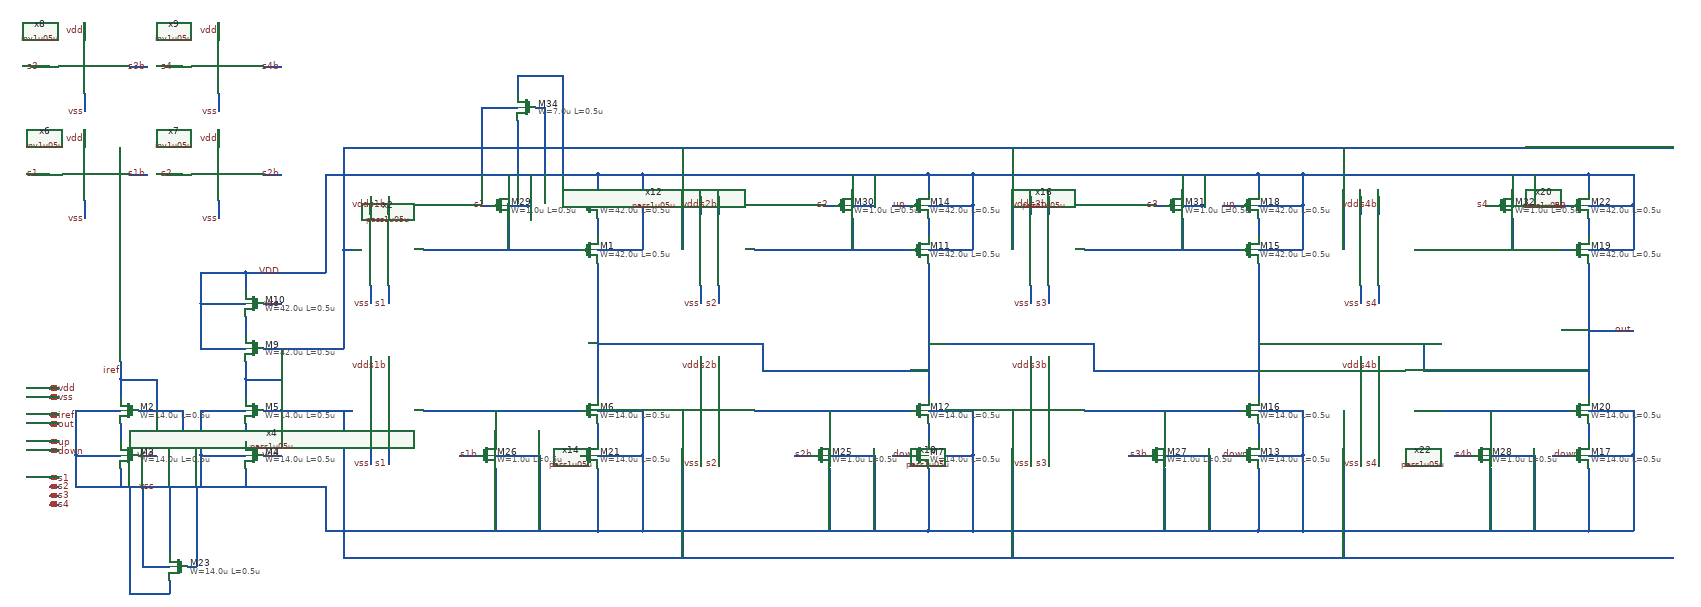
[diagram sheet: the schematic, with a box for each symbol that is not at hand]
v {xschem version=3.4.7 file_version=1.2}
G {}
K {}
V {}
S {}
E {}
P 4 1 -3240 -740 {}
N -2890 -1040 -2870 -1040 {lab=vdd}
N -2890 -1020 -2870 -1020 {lab=vss}
N -2890 -920 -2870 -920 {lab=up}
N -2890 -900 -2870 -900 {lab=down}
N -2890 -980 -2870 -980 {lab=iref}
N -2890 -960 -2870 -960 {lab=out}
N -2730 -860 -2730 -820 {lab=vss}
N -2820 -890 -2730 -890 {lab=vss}
N -2830 -890 -2820 -890 {lab=vss}
N -2830 -890 -2830 -820 {lab=vss}
N -2830 -820 -2730 -820 {lab=vss}
N -2830 -990 -2730 -990 {lab=vss}
N -2830 -990 -2830 -890 {lab=vss}
N -2730 -960 -2730 -920 {lab=#net1}
N -2690 -890 -2650 -890 {lab=vdd}
N -2690 -990 -2590 -990 {lab=iref}
N -2650 -1060 -2650 -990 {lab=iref}
N -2730 -1060 -2650 -1060 {lab=iref}
N -2730 -1060 -2730 -1020 {lab=iref}
N -2730 -1100 -2730 -1060 {lab=iref}
N -2450 -860 -2450 -820 {lab=vss}
N -2540 -890 -2450 -890 {lab=vss}
N -2550 -890 -2540 -890 {lab=vss}
N -2550 -890 -2550 -820 {lab=vss}
N -2550 -820 -2450 -820 {lab=vss}
N -2550 -990 -2450 -990 {lab=vss}
N -2550 -990 -2550 -890 {lab=vss}
N -2450 -960 -2450 -920 {lab=#net2}
N -2410 -890 -2370 -890 {lab=vdd}
N -2450 -1060 -2450 -1020 {lab=#net3}
N -2590 -990 -2590 -940 {lab=iref}
N -2590 -940 -2370 -940 {lab=iref}
N -2370 -990 -2370 -940 {lab=iref}
N -2410 -990 -2370 -990 {lab=iref}
N -1660 -860 -1660 -820 {lab=vss}
N -1660 -890 -1570 -890 {lab=vss}
N -1570 -890 -1560 -890 {lab=vss}
N -1560 -890 -1560 -820 {lab=vss}
N -1660 -990 -1560 -990 {lab=vss}
N -1560 -990 -1560 -890 {lab=vss}
N -1660 -960 -1660 -920 {lab=#net4}
N -1740 -890 -1700 -890 {lab=down}
N -1740 -990 -1700 -990 {lab=#net5}
N -2730 -820 -2550 -820 {lab=vss}
N -2370 -990 -2350 -990 {lab=iref}
N -2450 -820 -2270 -820 {lab=vss}
N -2410 -1130 -2310 -1130 {lab=#net3}
N -2450 -1100 -2450 -1060 {lab=#net3}
N -2450 -1060 -2370 -1060 {lab=#net3}
N -2370 -1130 -2370 -1060 {lab=#net3}
N -2450 -1200 -2450 -1160 {lab=#net6}
N -1660 -1420 -1660 -1380 {lab=#net7}
N -2410 -1230 -2370 -1230 {lab=vss}
N -1740 -1450 -1700 -1450 {lab=up}
N -2550 -1130 -2450 -1130 {lab=VDD}
N -2550 -1230 -2550 -1130 {lab=VDD}
N -2550 -1230 -2450 -1230 {lab=VDD}
N -1660 -1350 -1560 -1350 {lab=VDD}
N -1560 -1450 -1560 -1350 {lab=VDD}
N -1660 -1450 -1560 -1450 {lab=VDD}
N -1560 -1520 -1560 -1450 {lab=VDD}
N -1660 -1520 -1560 -1520 {lab=VDD}
N -1660 -1520 -1660 -1480 {lab=VDD}
N -2450 -1300 -2270 -1300 {lab=VDD}
N -2450 -1300 -2450 -1260 {lab=VDD}
N -2550 -1300 -2450 -1300 {lab=VDD}
N -2550 -1300 -2550 -1230 {lab=VDD}
N 560 -1170 660 -1170 {lab=out}
N -2350 -990 -2310 -990 {lab=iref}
N -2270 -1520 -2270 -1300 {lab=VDD}
N -2130 -1270 -2130 -1230 {lab=s1}
N -2170 -1270 -2170 -1230 {lab=vss}
N -2170 -1470 -2170 -1430 {lab=vdd}
N -2130 -1470 -2130 -1430 {lab=s1b}
N -2130 -910 -2130 -870 {lab=s1}
N -2130 -1110 -2130 -1070 {lab=s1b}
N -1560 -820 -1560 -780 {lab=vss}
N -1660 -820 -1660 -780 {lab=vss}
N -2310 -1130 -2230 -1130 {lab=#net3}
N -2230 -1350 -2230 -1130 {lab=#net3}
N -2230 -1350 -2210 -1350 {lab=#net3}
N -2050 -1350 -1770 -1350 {lab=#net8}
N -2310 -990 -2210 -990 {lab=iref}
N -2270 -1520 -1730 -1520 {lab=VDD}
N -2050 -990 -1950 -990 {lab=#net5}
N -2270 -820 -2270 -720 {lab=vss}
N -2270 -720 -1660 -720 {lab=vss}
N -1660 -780 -1660 -720 {lab=vss}
N -1560 -780 -1560 -720 {lab=vss}
N -1660 -720 -1560 -720 {lab=vss}
N -1950 -990 -1740 -990 {lab=#net5}
N -1730 -1520 -1660 -1520 {lab=VDD}
N -1770 -1350 -1700 -1350 {lab=#net8}
N -1660 -1320 -1660 -1020 {lab=out}
N -2890 -800 -2870 -800 {lab=s3}
N -2890 -780 -2870 -780 {lab=s4}
N -2890 -840 -2870 -840 {lab=s1}
N -2890 -820 -2870 -820 {lab=s2}
N -2710 -1520 -2670 -1520 {lab=s1b}
N -2930 -1520 -2890 -1520 {lab=s1}
N -2410 -1520 -2370 -1520 {lab=s2b}
N -2630 -1520 -2590 -1520 {lab=s2}
N -2710 -1760 -2670 -1760 {lab=s3b}
N -2810 -1860 -2810 -1820 {lab=vdd}
N -2810 -1700 -2810 -1660 {lab=vss}
N -2930 -1760 -2890 -1760 {lab=s3}
N -2410 -1760 -2370 -1760 {lab=s4b}
N -2630 -1760 -2590 -1760 {lab=s4}
N -920 -860 -920 -820 {lab=vss}
N -920 -890 -830 -890 {lab=vss}
N -830 -890 -820 -890 {lab=vss}
N -820 -890 -820 -820 {lab=vss}
N -920 -990 -820 -990 {lab=vss}
N -820 -990 -820 -890 {lab=vss}
N -920 -960 -920 -920 {lab=#net9}
N -1000 -890 -960 -890 {lab=down}
N -1000 -990 -960 -990 {lab=#net10}
N -920 -1420 -920 -1380 {lab=#net11}
N -1000 -1450 -960 -1450 {lab=up}
N -920 -1350 -820 -1350 {lab=VDD}
N -820 -1450 -820 -1350 {lab=VDD}
N -920 -1450 -820 -1450 {lab=VDD}
N -820 -1520 -820 -1450 {lab=VDD}
N -920 -1520 -820 -1520 {lab=VDD}
N -920 -1520 -920 -1480 {lab=VDD}
N -1390 -1270 -1390 -1230 {lab=s2}
N -1390 -1470 -1390 -1430 {lab=s2b}
N -1390 -910 -1390 -870 {lab=s2}
N -1390 -1110 -1390 -1070 {lab=s2b}
N -820 -820 -820 -780 {lab=vss}
N -920 -820 -920 -780 {lab=vss}
N -1310 -1350 -1030 -1350 {lab=#net12}
N -1310 -990 -1210 -990 {lab=#net10}
N -920 -780 -920 -720 {lab=vss}
N -820 -780 -820 -720 {lab=vss}
N -920 -720 -820 -720 {lab=vss}
N -1210 -990 -1000 -990 {lab=#net10}
N -990 -1520 -920 -1520 {lab=VDD}
N -1030 -1350 -960 -1350 {lab=#net12}
N -920 -1320 -920 -1020 {lab=out}
N -180 -860 -180 -820 {lab=vss}
N -180 -890 -90 -890 {lab=vss}
N -90 -890 -80 -890 {lab=vss}
N -80 -890 -80 -820 {lab=vss}
N -180 -990 -80 -990 {lab=vss}
N -80 -990 -80 -890 {lab=vss}
N -180 -960 -180 -920 {lab=#net13}
N -260 -890 -220 -890 {lab=down}
N -260 -990 -220 -990 {lab=#net14}
N -180 -1420 -180 -1380 {lab=#net15}
N -260 -1450 -220 -1450 {lab=up}
N -180 -1350 -80 -1350 {lab=VDD}
N -80 -1450 -80 -1350 {lab=VDD}
N -180 -1450 -80 -1450 {lab=VDD}
N -80 -1520 -80 -1450 {lab=VDD}
N -180 -1520 -80 -1520 {lab=VDD}
N -180 -1520 -180 -1480 {lab=VDD}
N -650 -1270 -650 -1230 {lab=s3}
N -650 -1470 -650 -1430 {lab=s3b}
N -650 -910 -650 -870 {lab=s3}
N -650 -1110 -650 -1070 {lab=s3b}
N -80 -820 -80 -780 {lab=vss}
N -180 -820 -180 -780 {lab=vss}
N -570 -1350 -290 -1350 {lab=#net16}
N -570 -990 -470 -990 {lab=#net14}
N -180 -780 -180 -720 {lab=vss}
N -80 -780 -80 -720 {lab=vss}
N -180 -720 -80 -720 {lab=vss}
N -470 -990 -260 -990 {lab=#net14}
N -250 -1520 -180 -1520 {lab=VDD}
N -290 -1350 -220 -1350 {lab=#net16}
N -180 -1320 -180 -1020 {lab=out}
N 560 -860 560 -820 {lab=vss}
N 560 -890 650 -890 {lab=vss}
N 650 -890 660 -890 {lab=vss}
N 660 -890 660 -820 {lab=vss}
N 560 -990 660 -990 {lab=vss}
N 660 -990 660 -890 {lab=vss}
N 560 -960 560 -920 {lab=#net17}
N 480 -890 520 -890 {lab=down}
N 480 -990 520 -990 {lab=#net18}
N 560 -1420 560 -1380 {lab=#net19}
N 480 -1450 520 -1450 {lab=#net20}
N 560 -1350 660 -1350 {lab=VDD}
N 660 -1450 660 -1350 {lab=VDD}
N 560 -1450 660 -1450 {lab=VDD}
N 660 -1520 660 -1450 {lab=VDD}
N 560 -1520 660 -1520 {lab=VDD}
N 560 -1520 560 -1480 {lab=VDD}
N 90 -1270 90 -1230 {lab=s4}
N 90 -1470 90 -1430 {lab=s4b}
N 90 -910 90 -870 {lab=s4}
N 90 -1110 90 -1070 {lab=s4b}
N 660 -820 660 -780 {lab=vss}
N 560 -820 560 -780 {lab=vss}
N 170 -1350 450 -1350 {lab=#net21}
N 170 -990 270 -990 {lab=#net18}
N 560 -780 560 -720 {lab=vss}
N 660 -780 660 -720 {lab=vss}
N 560 -720 660 -720 {lab=vss}
N 270 -990 480 -990 {lab=#net18}
N 490 -1520 560 -1520 {lab=VDD}
N 450 -1350 520 -1350 {lab=#net21}
N 560 -1320 560 -1020 {lab=out}
N -1560 -720 -920 -720 {lab=vss}
N -820 -720 -180 -720 {lab=vss}
N -80 -720 560 -720 {lab=vss}
N -1560 -1520 -990 -1520 {lab=VDD}
N -820 -1520 -250 -1520 {lab=VDD}
N -80 -1520 490 -1520 {lab=VDD}
N -2230 -1580 -2230 -1350 {lab=#net3}
N 10 -1580 10 -1350 {lab=#net3}
N -730 -1580 -730 -1350 {lab=#net3}
N -1470 -1580 -1470 -1350 {lab=#net3}
N -2230 -990 -2230 -660 {lab=iref}
N 10 -990 10 -660 {lab=iref}
N -730 -990 -730 -660 {lab=iref}
N -1470 -990 -1470 -660 {lab=iref}
N -1660 -1140 -1290 -1140 {lab=out}
N -1290 -1140 -1290 -1080 {lab=out}
N -1290 -1080 -920 -1080 {lab=out}
N -920 -1140 -550 -1140 {lab=out}
N -550 -1140 -550 -1080 {lab=out}
N -550 -1080 -180 -1080 {lab=out}
N -180 -1140 190 -1140 {lab=out}
N 190 -1140 190 -1080 {lab=out}
N 190 -1080 560 -1080 {lab=out}
N -2230 -1580 750 -1580 {lab=#net3}
N -2230 -660 750 -660 {lab=iref}
N -2620 -820 -2620 -670 {lab=vss}
N -2680 -640 -2620 -640 {lab=vss}
N -2680 -820 -2680 -640 {lab=vss}
N -2580 -640 -2560 -640 {lab=vss}
N -2560 -820 -2560 -640 {lab=vss}
N -2620 -610 -2620 -580 {lab=vss}
N -2710 -580 -2620 -580 {lab=vss}
N -2710 -820 -2710 -580 {lab=vss}
N -1140 -890 -1050 -890 {lab=vss}
N -1050 -890 -1040 -890 {lab=vss}
N -1220 -890 -1180 -890 {lab=s2b}
N -1040 -890 -1040 -720 {lab=vss}
N -1140 -990 -1140 -920 {lab=#net10}
N -1140 -860 -1140 -720 {lab=vss}
N -1890 -890 -1800 -890 {lab=vss}
N -1800 -890 -1790 -890 {lab=vss}
N -1970 -890 -1930 -890 {lab=s1b}
N -1790 -890 -1790 -720 {lab=vss}
N -1890 -990 -1890 -920 {lab=#net5}
N -1890 -860 -1890 -720 {lab=vss}
N -390 -890 -300 -890 {lab=vss}
N -300 -890 -290 -890 {lab=vss}
N -470 -890 -430 -890 {lab=s3b}
N -290 -890 -290 -720 {lab=vss}
N -390 -990 -390 -920 {lab=#net14}
N -390 -860 -390 -720 {lab=vss}
N 340 -890 430 -890 {lab=vss}
N 430 -890 440 -890 {lab=vss}
N 260 -890 300 -890 {lab=s4b}
N 440 -890 440 -720 {lab=vss}
N 340 -990 340 -920 {lab=#net18}
N 340 -860 340 -720 {lab=vss}
N -1860 -1450 -1810 -1450 {lab=VDD}
N -1810 -1520 -1810 -1450 {lab=VDD}
N -1860 -1420 -1860 -1350 {lab=#net8}
N -1860 -1520 -1860 -1480 {lab=VDD}
N -1920 -1450 -1900 -1450 {lab=s1}
N -1090 -1450 -1040 -1450 {lab=VDD}
N -1040 -1520 -1040 -1450 {lab=VDD}
N -1090 -1420 -1090 -1350 {lab=#net12}
N -1090 -1520 -1090 -1480 {lab=VDD}
N -1150 -1450 -1130 -1450 {lab=s2}
N -350 -1450 -300 -1450 {lab=VDD}
N -300 -1520 -300 -1450 {lab=VDD}
N -350 -1420 -350 -1350 {lab=#net16}
N -350 -1520 -350 -1480 {lab=VDD}
N -410 -1450 -390 -1450 {lab=s3}
N 390 -1450 440 -1450 {lab=VDD}
N 440 -1520 440 -1450 {lab=VDD}
N 390 -1420 390 -1350 {lab=#net21}
N 390 -1520 390 -1480 {lab=VDD}
N 330 -1450 350 -1450 {lab=s4}
N -1840 -1740 -1840 -1700 {lab=VDD}
N -1920 -1670 -1840 -1670 {lab=VDD}
N -1920 -1670 -1920 -1520 {lab=VDD}
N -1840 -1640 -1840 -1520 {lab=VDD}
N -1840 -1740 -1740 -1740 {lab=VDD}
N -1740 -1740 -1740 -1520 {lab=VDD}
N -1800 -1670 -1780 -1670 {lab=VDD}
N -1780 -1670 -1780 -1520 {lab=VDD}
N -2230 -990 -2210 -990 {lab=iref}
N 50 -1270 50 -1230 {lab=vss}
N 50 -1470 50 -1430 {lab=vdd}
N -2810 -1620 -2810 -1580 {lab=vdd}
N -2810 -1460 -2810 -1420 {lab=vss}
N -2510 -1620 -2510 -1580 {lab=vdd}
N -2510 -1460 -2510 -1420 {lab=vss}
N -2510 -1860 -2510 -1820 {lab=vdd}
N -2510 -1700 -2510 -1660 {lab=vss}
N -2170 -910 -2170 -870 {lab=vss}
N -2170 -1110 -2170 -1070 {lab=vdd}
N -1430 -910 -1430 -870 {lab=vss}
N -1430 -1110 -1430 -1070 {lab=vdd}
N -1430 -1270 -1430 -1230 {lab=vss}
N -1430 -1470 -1430 -1430 {lab=vdd}
N -690 -1270 -690 -1230 {lab=vss}
N -690 -1470 -690 -1430 {lab=vdd}
N -690 -910 -690 -870 {lab=vss}
N -690 -1110 -690 -1070 {lab=vdd}
N 50 -910 50 -870 {lab=vss}
N 50 -1110 50 -1070 {lab=vdd}
C {devices/iopin.sym} -2890 -1040 0 1 {name=p2 lab=vdd}
C {devices/iopin.sym} -2890 -1020 0 1 {name=p3 lab=vss}
C {devices/iopin.sym} -2890 -920 0 1 {name=p5 lab=up}
C {devices/iopin.sym} -2890 -900 0 1 {name=p6 lab=down}
C {devices/iopin.sym} -2890 -980 0 1 {name=p1 lab=iref}
C {devices/iopin.sym} -2890 -960 0 1 {name=p4 lab=out}
C {devices/lab_wire.sym} -2650 -820 0 0 {name=p10 sig_type=std_logic lab=vss}
C {devices/lab_wire.sym} -2650 -890 0 0 {name=p7 sig_type=std_logic lab=vdd}
C {devices/lab_wire.sym} -2730 -1080 0 0 {name=p8 sig_type=std_logic lab=iref}
C {devices/lab_wire.sym} -2370 -890 0 0 {name=p11 sig_type=std_logic lab=vdd}
C {symbols/nfet_03v3.sym} -1680 -990 0 0 {name=M6
L=0.5u
W=14.0u
nf=2
m=1
ad="'int((nf+1)/2) * W/nf * 0.18u'"
pd="'2*int((nf+1)/2) * (W/nf + 0.18u)'"
as="'int((nf+2)/2) * W/nf * 0.18u'"
ps="'2*int((nf+2)/2) * (W/nf + 0.18u)'"
nrd="'0.18u / W'" nrs="'0.18u / W'"
sa=0 sb=0 sd=0
model=nfet_03v3
spiceprefix=X
}
C {devices/lab_wire.sym} -1740 -890 0 1 {name=p13 sig_type=std_logic lab=down}
C {symbols/pfet_03v3.sym} -1680 -1450 0 0 {name=M8
L=0.5u
W=42.0u
nf=6
m=1
ad="'int((nf+1)/2) * W/nf * 0.18u'"
pd="'2*int((nf+1)/2) * (W/nf + 0.18u)'"
as="'int((nf+2)/2) * W/nf * 0.18u'"
ps="'2*int((nf+2)/2) * (W/nf + 0.18u)'"
nrd="'0.18u / W'" nrs="'0.18u / W'"
sa=0 sb=0 sd=0
model=pfet_03v3
spiceprefix=X
}
C {symbols/pfet_03v3.sym} -2430 -1230 0 1 {name=M10
L=0.5u
W=42.0u
nf=6
m=1
ad="'int((nf+1)/2) * W/nf * 0.18u'"
pd="'2*int((nf+1)/2) * (W/nf + 0.18u)'"
as="'int((nf+2)/2) * W/nf * 0.18u'"
ps="'2*int((nf+2)/2) * (W/nf + 0.18u)'"
nrd="'0.18u / W'" nrs="'0.18u / W'"
sa=0 sb=0 sd=0
model=pfet_03v3
spiceprefix=X
}
C {devices/lab_wire.sym} -1740 -1450 0 1 {name=p9 sig_type=std_logic lab=up}
C {devices/lab_wire.sym} -2370 -1230 0 0 {name=p12 sig_type=std_logic lab=vss}
C {devices/lab_wire.sym} -2370 -1300 0 0 {name=p14 sig_type=std_logic lab=VDD}
C {devices/lab_wire.sym} 660 -1170 0 0 {name=p15 sig_type=std_logic lab=out}
C {libs/core_analog/pass1u05u/pass1u05u.sym} -2130 -1350 0 0 {name=x2}
C {devices/lab_wire.sym} -2170 -1230 0 0 {name=p22 sig_type=std_logic lab=vss}
C {devices/lab_wire.sym} -2170 -1450 0 0 {name=p23 sig_type=std_logic lab=vdd}
C {libs/core_analog/pass1u05u/pass1u05u.sym} -2130 -990 0 0 {name=x4}
C {devices/iopin.sym} -2890 -800 0 1 {name=p30 lab=s3}
C {devices/iopin.sym} -2890 -780 0 1 {name=p31 lab=s4}
C {devices/iopin.sym} -2890 -840 0 1 {name=p32 lab=s1}
C {devices/iopin.sym} -2890 -820 0 1 {name=p33 lab=s2}
C {libs/core_analog/inv1u05u/inv1u05u.sym} -2810 -1520 0 0 {name=x6}
C {devices/lab_wire.sym} -2910 -1520 0 0 {name=p36 sig_type=std_logic lab=s1}
C {devices/lab_wire.sym} -2670 -1520 0 0 {name=p37 sig_type=std_logic lab=s1b}
C {libs/core_analog/inv1u05u/inv1u05u.sym} -2510 -1520 0 0 {name=x7}
C {devices/lab_wire.sym} -2610 -1520 0 0 {name=p40 sig_type=std_logic lab=s2}
C {devices/lab_wire.sym} -2370 -1520 0 0 {name=p41 sig_type=std_logic lab=s2b}
C {libs/core_analog/inv1u05u/inv1u05u.sym} -2810 -1760 0 0 {name=x8}
C {devices/lab_wire.sym} -2910 -1760 0 0 {name=p44 sig_type=std_logic lab=s3}
C {devices/lab_wire.sym} -2670 -1760 0 0 {name=p45 sig_type=std_logic lab=s3b}
C {devices/lab_wire.sym} -2810 -1660 0 0 {name=p46 sig_type=std_logic lab=vss}
C {devices/lab_wire.sym} -2810 -1840 0 0 {name=p47 sig_type=std_logic lab=vdd}
C {libs/core_analog/inv1u05u/inv1u05u.sym} -2510 -1760 0 0 {name=x9}
C {devices/lab_wire.sym} -2610 -1760 0 0 {name=p48 sig_type=std_logic lab=s4}
C {devices/lab_wire.sym} -2370 -1760 0 0 {name=p49 sig_type=std_logic lab=s4b}
C {devices/lab_wire.sym} -2130 -1230 0 0 {name=p60 sig_type=std_logic lab=s1}
C {devices/lab_wire.sym} -2130 -1450 0 0 {name=p61 sig_type=std_logic lab=s1b}
C {devices/lab_wire.sym} -2130 -1090 0 0 {name=p64 sig_type=std_logic lab=s1b}
C {devices/lab_wire.sym} -2130 -870 0 0 {name=p66 sig_type=std_logic lab=s1}
C {symbols/nfet_03v3.sym} -940 -990 0 0 {name=M12
L=0.5u
W=14.0u
nf=2
m=2
ad="'int((nf+1)/2) * W/nf * 0.18u'"
pd="'2*int((nf+1)/2) * (W/nf + 0.18u)'"
as="'int((nf+2)/2) * W/nf * 0.18u'"
ps="'2*int((nf+2)/2) * (W/nf + 0.18u)'"
nrd="'0.18u / W'" nrs="'0.18u / W'"
sa=0 sb=0 sd=0
model=nfet_03v3
spiceprefix=X
}
C {devices/lab_wire.sym} -1000 -890 0 1 {name=p68 sig_type=std_logic lab=down}
C {symbols/pfet_03v3.sym} -940 -1450 0 0 {name=M14
L=0.5u
W=42.0u
nf=6
m=2
ad="'int((nf+1)/2) * W/nf * 0.18u'"
pd="'2*int((nf+1)/2) * (W/nf + 0.18u)'"
as="'int((nf+2)/2) * W/nf * 0.18u'"
ps="'2*int((nf+2)/2) * (W/nf + 0.18u)'"
nrd="'0.18u / W'" nrs="'0.18u / W'"
sa=0 sb=0 sd=0
model=pfet_03v3
spiceprefix=X
}
C {libs/core_analog/pass1u05u/pass1u05u.sym} -1390 -1350 0 0 {name=x12}
C {libs/core_analog/pass1u05u/pass1u05u.sym} -1390 -990 0 0 {name=x14}
C {devices/lab_wire.sym} -1390 -1230 0 0 {name=p80 sig_type=std_logic lab=s2}
C {devices/lab_wire.sym} -1390 -1450 0 0 {name=p81 sig_type=std_logic lab=s2b}
C {devices/lab_wire.sym} -1390 -1090 0 0 {name=p84 sig_type=std_logic lab=s2b}
C {devices/lab_wire.sym} -1390 -870 0 0 {name=p86 sig_type=std_logic lab=s2}
C {symbols/nfet_03v3.sym} -200 -990 0 0 {name=M16
L=0.5u
W=14.0u
nf=2
m=4
ad="'int((nf+1)/2) * W/nf * 0.18u'"
pd="'2*int((nf+1)/2) * (W/nf + 0.18u)'"
as="'int((nf+2)/2) * W/nf * 0.18u'"
ps="'2*int((nf+2)/2) * (W/nf + 0.18u)'"
nrd="'0.18u / W'" nrs="'0.18u / W'"
sa=0 sb=0 sd=0
model=nfet_03v3
spiceprefix=X
}
C {devices/lab_wire.sym} -260 -890 0 1 {name=p88 sig_type=std_logic lab=down}
C {symbols/pfet_03v3.sym} -200 -1450 0 0 {name=M18
L=0.5u
W=42.0u
nf=6
m=4
ad="'int((nf+1)/2) * W/nf * 0.18u'"
pd="'2*int((nf+1)/2) * (W/nf + 0.18u)'"
as="'int((nf+2)/2) * W/nf * 0.18u'"
ps="'2*int((nf+2)/2) * (W/nf + 0.18u)'"
nrd="'0.18u / W'" nrs="'0.18u / W'"
sa=0 sb=0 sd=0
model=pfet_03v3
spiceprefix=X
}
C {libs/core_analog/pass1u05u/pass1u05u.sym} -650 -1350 0 0 {name=x16}
C {libs/core_analog/pass1u05u/pass1u05u.sym} -650 -990 0 0 {name=x18}
C {devices/lab_wire.sym} -650 -1230 0 0 {name=p100 sig_type=std_logic lab=s3}
C {devices/lab_wire.sym} -650 -1450 0 0 {name=p101 sig_type=std_logic lab=s3b}
C {devices/lab_wire.sym} -650 -1090 0 0 {name=p104 sig_type=std_logic lab=s3b}
C {devices/lab_wire.sym} -650 -870 0 0 {name=p106 sig_type=std_logic lab=s3}
C {symbols/pfet_03v3.sym} 540 -1350 0 0 {name=M19
L=0.5u
W=42.0u
nf=6
m=8
ad="'int((nf+1)/2) * W/nf * 0.18u'"
pd="'2*int((nf+1)/2) * (W/nf + 0.18u)'"
as="'int((nf+2)/2) * W/nf * 0.18u'"
ps="'2*int((nf+2)/2) * (W/nf + 0.18u)'"
nrd="'0.18u / W'" nrs="'0.18u / W'"
sa=0 sb=0 sd=0
model=pfet_03v3
spiceprefix=X
}
C {symbols/nfet_03v3.sym} 540 -990 0 0 {name=M20
L=0.5u
W=14.0u
nf=2
m=8
ad="'int((nf+1)/2) * W/nf * 0.18u'"
pd="'2*int((nf+1)/2) * (W/nf + 0.18u)'"
as="'int((nf+2)/2) * W/nf * 0.18u'"
ps="'2*int((nf+2)/2) * (W/nf + 0.18u)'"
nrd="'0.18u / W'" nrs="'0.18u / W'"
sa=0 sb=0 sd=0
model=nfet_03v3
spiceprefix=X
}
C {devices/lab_wire.sym} 480 -890 0 1 {name=p108 sig_type=std_logic lab=down}
C {symbols/pfet_03v3.sym} 540 -1450 0 0 {name=M22
L=0.5u
W=42.0u
nf=6
m=8
ad="'int((nf+1)/2) * W/nf * 0.18u'"
pd="'2*int((nf+1)/2) * (W/nf + 0.18u)'"
as="'int((nf+2)/2) * W/nf * 0.18u'"
ps="'2*int((nf+2)/2) * (W/nf + 0.18u)'"
nrd="'0.18u / W'" nrs="'0.18u / W'"
sa=0 sb=0 sd=0
model=pfet_03v3
spiceprefix=X
}
C {libs/core_analog/pass1u05u/pass1u05u.sym} 90 -1350 0 0 {name=x20}
C {libs/core_analog/pass1u05u/pass1u05u.sym} 90 -990 0 0 {name=x22}
C {devices/lab_wire.sym} 90 -1230 0 0 {name=p120 sig_type=std_logic lab=s4}
C {devices/lab_wire.sym} 90 -1450 0 0 {name=p121 sig_type=std_logic lab=s4b}
C {devices/lab_wire.sym} 90 -1090 0 0 {name=p124 sig_type=std_logic lab=s4b}
C {devices/lab_wire.sym} 90 -870 0 0 {name=p126 sig_type=std_logic lab=s4}
C {symbols/nfet_03v3.sym} -2710 -990 0 1 {name=M2
L=0.5u
W=14.0u
nf=2
m=1
ad="'int((nf+1)/2) * W/nf * 0.18u'"
pd="'2*int((nf+1)/2) * (W/nf + 0.18u)'"
as="'int((nf+2)/2) * W/nf * 0.18u'"
ps="'2*int((nf+2)/2) * (W/nf + 0.18u)'"
nrd="'0.18u / W'" nrs="'0.18u / W'"
sa=0 sb=0 sd=0
model=nfet_03v3
spiceprefix=X
}
C {symbols/pfet_03v3.sym} -2430 -1130 0 1 {name=M9
L=0.5u
W=42.0u
nf=6
m=1
ad="'int((nf+1)/2) * W/nf * 0.18u'"
pd="'2*int((nf+1)/2) * (W/nf + 0.18u)'"
as="'int((nf+2)/2) * W/nf * 0.18u'"
ps="'2*int((nf+2)/2) * (W/nf + 0.18u)'"
nrd="'0.18u / W'" nrs="'0.18u / W'"
sa=0 sb=0 sd=0
model=pfet_03v3
spiceprefix=X
}
C {symbols/pfet_03v3.sym} -1680 -1350 0 0 {name=M1
L=0.5u
W=42.0u
nf=6
m=1
ad="'int((nf+1)/2) * W/nf * 0.18u'"
pd="'2*int((nf+1)/2) * (W/nf + 0.18u)'"
as="'int((nf+2)/2) * W/nf * 0.18u'"
ps="'2*int((nf+2)/2) * (W/nf + 0.18u)'"
nrd="'0.18u / W'" nrs="'0.18u / W'"
sa=0 sb=0 sd=0
model=pfet_03v3
spiceprefix=X
}
C {symbols/pfet_03v3.sym} -940 -1350 0 0 {name=M11
L=0.5u
W=42.0u
nf=6
m=2
ad="'int((nf+1)/2) * W/nf * 0.18u'"
pd="'2*int((nf+1)/2) * (W/nf + 0.18u)'"
as="'int((nf+2)/2) * W/nf * 0.18u'"
ps="'2*int((nf+2)/2) * (W/nf + 0.18u)'"
nrd="'0.18u / W'" nrs="'0.18u / W'"
sa=0 sb=0 sd=0
model=pfet_03v3
spiceprefix=X
}
C {symbols/pfet_03v3.sym} -200 -1350 0 0 {name=M15
L=0.5u
W=42.0u
nf=6
m=4
ad="'int((nf+1)/2) * W/nf * 0.18u'"
pd="'2*int((nf+1)/2) * (W/nf + 0.18u)'"
as="'int((nf+2)/2) * W/nf * 0.18u'"
ps="'2*int((nf+2)/2) * (W/nf + 0.18u)'"
nrd="'0.18u / W'" nrs="'0.18u / W'"
sa=0 sb=0 sd=0
model=pfet_03v3
spiceprefix=X
}
C {symbols/nfet_03v3.sym} -2710 -890 0 1 {name=M3
L=0.5u
W=14.0u
nf=2
m=1
ad="'int((nf+1)/2) * W/nf * 0.18u'"
pd="'2*int((nf+1)/2) * (W/nf + 0.18u)'"
as="'int((nf+2)/2) * W/nf * 0.18u'"
ps="'2*int((nf+2)/2) * (W/nf + 0.18u)'"
nrd="'0.18u / W'" nrs="'0.18u / W'"
sa=0 sb=0 sd=0
model=nfet_03v3
spiceprefix=X
}
C {symbols/nfet_03v3.sym} -2430 -890 0 1 {name=M4
L=0.5u
W=14.0u
nf=2
m=1
ad="'int((nf+1)/2) * W/nf * 0.18u'"
pd="'2*int((nf+1)/2) * (W/nf + 0.18u)'"
as="'int((nf+2)/2) * W/nf * 0.18u'"
ps="'2*int((nf+2)/2) * (W/nf + 0.18u)'"
nrd="'0.18u / W'" nrs="'0.18u / W'"
sa=0 sb=0 sd=0
model=nfet_03v3
spiceprefix=X
}
C {symbols/nfet_03v3.sym} -2430 -990 0 1 {name=M5
L=0.5u
W=14.0u
nf=2
m=1
ad="'int((nf+1)/2) * W/nf * 0.18u'"
pd="'2*int((nf+1)/2) * (W/nf + 0.18u)'"
as="'int((nf+2)/2) * W/nf * 0.18u'"
ps="'2*int((nf+2)/2) * (W/nf + 0.18u)'"
nrd="'0.18u / W'" nrs="'0.18u / W'"
sa=0 sb=0 sd=0
model=nfet_03v3
spiceprefix=X
}
C {symbols/nfet_03v3.sym} -1680 -890 0 0 {name=M21
L=0.5u
W=14.0u
nf=2
m=1
ad="'int((nf+1)/2) * W/nf * 0.18u'"
pd="'2*int((nf+1)/2) * (W/nf + 0.18u)'"
as="'int((nf+2)/2) * W/nf * 0.18u'"
ps="'2*int((nf+2)/2) * (W/nf + 0.18u)'"
nrd="'0.18u / W'" nrs="'0.18u / W'"
sa=0 sb=0 sd=0
model=nfet_03v3
spiceprefix=X
}
C {symbols/nfet_03v3.sym} -940 -890 0 0 {name=M7
L=0.5u
W=14.0u
nf=2
m=2
ad="'int((nf+1)/2) * W/nf * 0.18u'"
pd="'2*int((nf+1)/2) * (W/nf + 0.18u)'"
as="'int((nf+2)/2) * W/nf * 0.18u'"
ps="'2*int((nf+2)/2) * (W/nf + 0.18u)'"
nrd="'0.18u / W'" nrs="'0.18u / W'"
sa=0 sb=0 sd=0
model=nfet_03v3
spiceprefix=X
}
C {symbols/nfet_03v3.sym} -200 -890 0 0 {name=M13
L=0.5u
W=14.0u
nf=2
m=4
ad="'int((nf+1)/2) * W/nf * 0.18u'"
pd="'2*int((nf+1)/2) * (W/nf + 0.18u)'"
as="'int((nf+2)/2) * W/nf * 0.18u'"
ps="'2*int((nf+2)/2) * (W/nf + 0.18u)'"
nrd="'0.18u / W'" nrs="'0.18u / W'"
sa=0 sb=0 sd=0
model=nfet_03v3
spiceprefix=X
}
C {symbols/nfet_03v3.sym} 540 -890 0 0 {name=M17
L=0.5u
W=14.0u
nf=2
m=8
ad="'int((nf+1)/2) * W/nf * 0.18u'"
pd="'2*int((nf+1)/2) * (W/nf + 0.18u)'"
as="'int((nf+2)/2) * W/nf * 0.18u'"
ps="'2*int((nf+2)/2) * (W/nf + 0.18u)'"
nrd="'0.18u / W'" nrs="'0.18u / W'"
sa=0 sb=0 sd=0
model=nfet_03v3
spiceprefix=X
}
C {symbols/nfet_03v3.sym} -2600 -640 0 1 {name=M23
L=0.5u
W=14.0u
nf=2
m=12
ad="'int((nf+1)/2) * W/nf * 0.18u'"
pd="'2*int((nf+1)/2) * (W/nf + 0.18u)'"
as="'int((nf+2)/2) * W/nf * 0.18u'"
ps="'2*int((nf+2)/2) * (W/nf + 0.18u)'"
nrd="'0.18u / W'" nrs="'0.18u / W'"
sa=0 sb=0 sd=0
model=nfet_03v3
spiceprefix=X
}
C {devices/lab_wire.sym} -1220 -890 0 1 {name=p20 sig_type=std_logic lab=s2b
}
C {devices/lab_wire.sym} -1970 -890 0 1 {name=p21 sig_type=std_logic lab=s1b
}
C {symbols/nfet_03v3.sym} -1910 -890 0 0 {name=M26
L=0.5u
W=1.0u
nf=1
m=1
ad="'int((nf+1)/2) * W/nf * 0.18u'"
pd="'2*int((nf+1)/2) * (W/nf + 0.18u)'"
as="'int((nf+2)/2) * W/nf * 0.18u'"
ps="'2*int((nf+2)/2) * (W/nf + 0.18u)'"
nrd="'0.18u / W'" nrs="'0.18u / W'"
sa=0 sb=0 sd=0
model=nfet_03v3
spiceprefix=X
}
C {devices/lab_wire.sym} -470 -890 0 1 {name=p24 sig_type=std_logic lab=s3b
}
C {devices/lab_wire.sym} 260 -890 0 1 {name=p25 sig_type=std_logic lab=s4b
}
C {symbols/pfet_03v3.sym} -1880 -1450 0 0 {name=M29
L=0.5u
W=1.0u
nf=1
m=1
ad="'int((nf+1)/2) * W/nf * 0.18u'"
pd="'2*int((nf+1)/2) * (W/nf + 0.18u)'"
as="'int((nf+2)/2) * W/nf * 0.18u'"
ps="'2*int((nf+2)/2) * (W/nf + 0.18u)'"
nrd="'0.18u / W'" nrs="'0.18u / W'"
sa=0 sb=0 sd=0
model=pfet_03v3
spiceprefix=X
}
C {devices/lab_wire.sym} -1910 -1450 0 0 {name=p26 sig_type=std_logic lab=s1}
C {devices/lab_wire.sym} -1140 -1450 0 0 {name=p29 sig_type=std_logic lab=s2}
C {devices/lab_wire.sym} -400 -1450 0 0 {name=p34 sig_type=std_logic lab=s3}
C {devices/lab_wire.sym} 340 -1450 0 0 {name=p35 sig_type=std_logic lab=s4}
C {symbols/pfet_03v3.sym} -1820 -1670 0 1 {name=M34
L=0.5u
W=7.0u
nf=1
m=24
ad="'int((nf+1)/2) * W/nf * 0.18u'"
pd="'2*int((nf+1)/2) * (W/nf + 0.18u)'"
as="'int((nf+2)/2) * W/nf * 0.18u'"
ps="'2*int((nf+2)/2) * (W/nf + 0.18u)'"
nrd="'0.18u / W'" nrs="'0.18u / W'"
sa=0 sb=0 sd=0
model=pfet_03v3
spiceprefix=X
}
C {symbols/nfet_03v3.sym} -1160 -890 0 0 {name=M25
L=0.5u
W=1.0u
nf=1
m=1
ad="'int((nf+1)/2) * W/nf * 0.18u'"
pd="'2*int((nf+1)/2) * (W/nf + 0.18u)'"
as="'int((nf+2)/2) * W/nf * 0.18u'"
ps="'2*int((nf+2)/2) * (W/nf + 0.18u)'"
nrd="'0.18u / W'" nrs="'0.18u / W'"
sa=0 sb=0 sd=0
model=nfet_03v3
spiceprefix=X
}
C {symbols/nfet_03v3.sym} -410 -890 0 0 {name=M27
L=0.5u
W=1.0u
nf=1
m=1
ad="'int((nf+1)/2) * W/nf * 0.18u'"
pd="'2*int((nf+1)/2) * (W/nf + 0.18u)'"
as="'int((nf+2)/2) * W/nf * 0.18u'"
ps="'2*int((nf+2)/2) * (W/nf + 0.18u)'"
nrd="'0.18u / W'" nrs="'0.18u / W'"
sa=0 sb=0 sd=0
model=nfet_03v3
spiceprefix=X
}
C {symbols/nfet_03v3.sym} 320 -890 0 0 {name=M28
L=0.5u
W=1.0u
nf=1
m=1
ad="'int((nf+1)/2) * W/nf * 0.18u'"
pd="'2*int((nf+1)/2) * (W/nf + 0.18u)'"
as="'int((nf+2)/2) * W/nf * 0.18u'"
ps="'2*int((nf+2)/2) * (W/nf + 0.18u)'"
nrd="'0.18u / W'" nrs="'0.18u / W'"
sa=0 sb=0 sd=0
model=nfet_03v3
spiceprefix=X
}
C {symbols/pfet_03v3.sym} -1110 -1450 0 0 {name=M30
L=0.5u
W=1.0u
nf=1
m=1
ad="'int((nf+1)/2) * W/nf * 0.18u'"
pd="'2*int((nf+1)/2) * (W/nf + 0.18u)'"
as="'int((nf+2)/2) * W/nf * 0.18u'"
ps="'2*int((nf+2)/2) * (W/nf + 0.18u)'"
nrd="'0.18u / W'" nrs="'0.18u / W'"
sa=0 sb=0 sd=0
model=pfet_03v3
spiceprefix=X
}
C {symbols/pfet_03v3.sym} -370 -1450 0 0 {name=M31
L=0.5u
W=1.0u
nf=1
m=1
ad="'int((nf+1)/2) * W/nf * 0.18u'"
pd="'2*int((nf+1)/2) * (W/nf + 0.18u)'"
as="'int((nf+2)/2) * W/nf * 0.18u'"
ps="'2*int((nf+2)/2) * (W/nf + 0.18u)'"
nrd="'0.18u / W'" nrs="'0.18u / W'"
sa=0 sb=0 sd=0
model=pfet_03v3
spiceprefix=X
}
C {symbols/pfet_03v3.sym} 370 -1450 0 0 {name=M32
L=0.5u
W=1.0u
nf=1
m=1
ad="'int((nf+1)/2) * W/nf * 0.18u'"
pd="'2*int((nf+1)/2) * (W/nf + 0.18u)'"
as="'int((nf+2)/2) * W/nf * 0.18u'"
ps="'2*int((nf+2)/2) * (W/nf + 0.18u)'"
nrd="'0.18u / W'" nrs="'0.18u / W'"
sa=0 sb=0 sd=0
model=pfet_03v3
spiceprefix=X
}
C {devices/lab_wire.sym} 50 -1230 0 0 {name=p62 sig_type=std_logic lab=vss}
C {devices/lab_wire.sym} 50 -1450 0 0 {name=p63 sig_type=std_logic lab=vdd}
C {devices/lab_wire.sym} -2810 -1420 0 0 {name=p18 sig_type=std_logic lab=vss}
C {devices/lab_wire.sym} -2810 -1600 0 0 {name=p19 sig_type=std_logic lab=vdd}
C {devices/lab_wire.sym} -2510 -1420 0 0 {name=p42 sig_type=std_logic lab=vss}
C {devices/lab_wire.sym} -2510 -1600 0 0 {name=p43 sig_type=std_logic lab=vdd}
C {devices/lab_wire.sym} -2510 -1660 0 0 {name=p50 sig_type=std_logic lab=vss}
C {devices/lab_wire.sym} -2510 -1840 0 0 {name=p51 sig_type=std_logic lab=vdd}
C {devices/lab_wire.sym} -2170 -870 0 0 {name=p27 sig_type=std_logic lab=vss}
C {devices/lab_wire.sym} -2170 -1090 0 0 {name=p28 sig_type=std_logic lab=vdd}
C {devices/lab_wire.sym} -1430 -870 0 0 {name=p52 sig_type=std_logic lab=vss}
C {devices/lab_wire.sym} -1430 -1090 0 0 {name=p53 sig_type=std_logic lab=vdd}
C {devices/lab_wire.sym} -1430 -1230 0 0 {name=p54 sig_type=std_logic lab=vss}
C {devices/lab_wire.sym} -1430 -1450 0 0 {name=p55 sig_type=std_logic lab=vdd}
C {devices/lab_wire.sym} -690 -1230 0 0 {name=p56 sig_type=std_logic lab=vss}
C {devices/lab_wire.sym} -690 -1450 0 0 {name=p57 sig_type=std_logic lab=vdd}
C {devices/lab_wire.sym} -690 -870 0 0 {name=p58 sig_type=std_logic lab=vss}
C {devices/lab_wire.sym} -690 -1090 0 0 {name=p59 sig_type=std_logic lab=vdd}
C {devices/lab_wire.sym} 50 -870 0 0 {name=p65 sig_type=std_logic lab=vss}
C {devices/lab_wire.sym} 50 -1090 0 0 {name=p67 sig_type=std_logic lab=vdd}
C {devices/lab_wire.sym} -1000 -1450 0 1 {name=p16 sig_type=std_logic lab=up}
C {devices/lab_wire.sym} -260 -1450 0 1 {name=p17 sig_type=std_logic lab=up}
C {devices/lab_wire.sym} 480 -1450 0 1 {name=p38 sig_type=std_logic lab=up}
